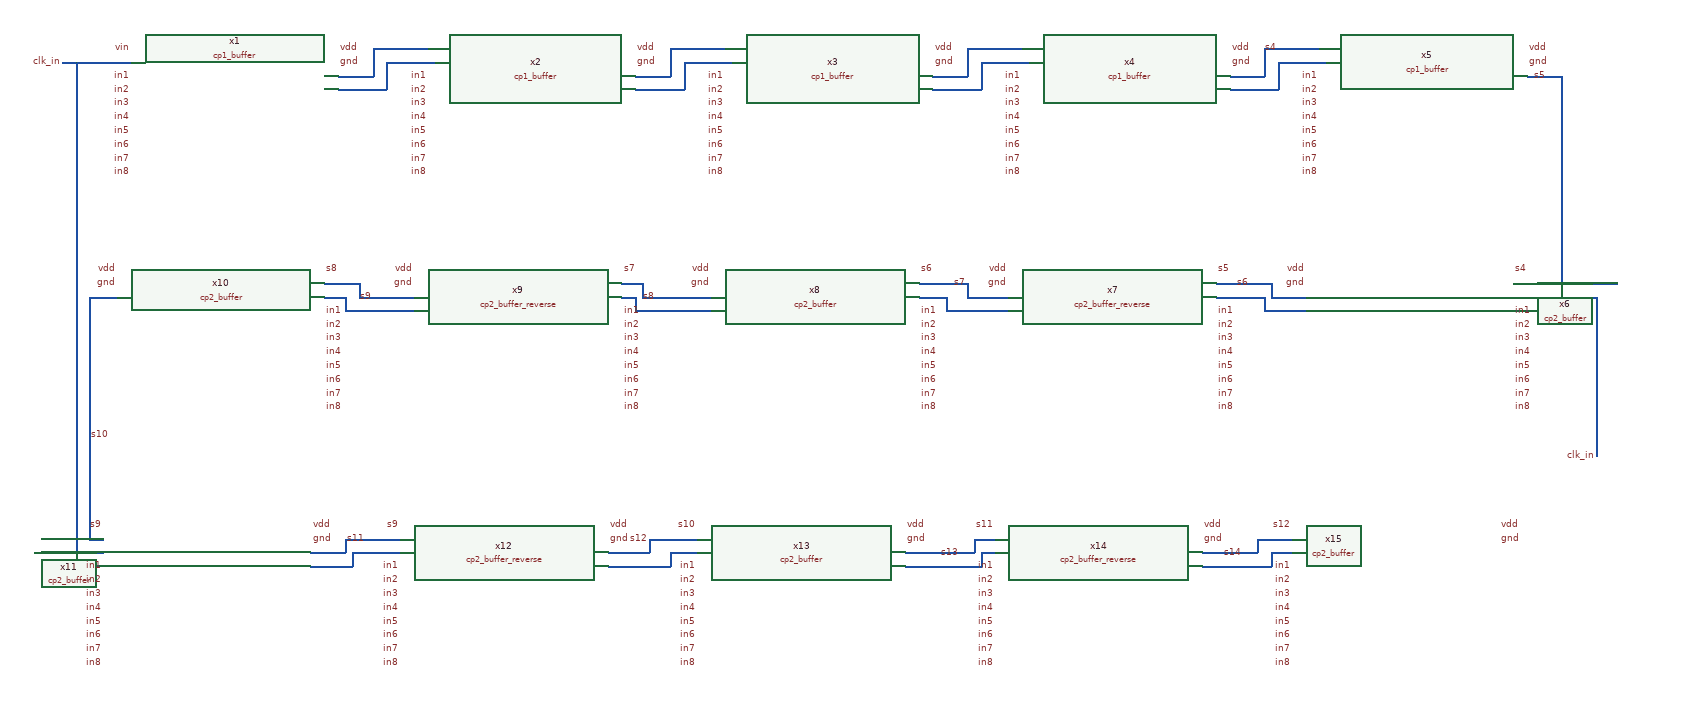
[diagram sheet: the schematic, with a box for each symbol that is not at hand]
v {xschem version=3.4.4 file_version=1.2
}
G {}
K {}
V {}
S {}
E {}
N -1940 -110 -1840 -110 {
lab=clk_in}
N -1540 -90 -1490 -90 {
lab=#net1}
N -1490 -110 -1490 -90 {
lab=#net1}
N -1490 -130 -1490 -110 {
lab=#net1}
N -1490 -130 -1410 -130 {
lab=#net1}
N -1540 -70 -1470 -70 {
lab=#net2}
N -1470 -110 -1470 -70 {
lab=#net2}
N -1470 -110 -1400 -110 {
lab=#net2}
N -1110 -90 -1060 -90 {
lab=#net3}
N -1060 -110 -1060 -90 {
lab=#net3}
N -1060 -130 -1060 -110 {
lab=#net3}
N -1060 -130 -980 -130 {
lab=#net3}
N -1110 -70 -1040 -70 {
lab=#net4}
N -1040 -110 -1040 -70 {
lab=#net4}
N -1040 -110 -970 -110 {
lab=#net4}
N -680 -90 -630 -90 {
lab=#net5}
N -630 -110 -630 -90 {
lab=#net5}
N -630 -130 -630 -110 {
lab=#net5}
N -630 -130 -550 -130 {
lab=#net5}
N -680 -70 -610 -70 {
lab=#net6}
N -610 -110 -610 -70 {
lab=#net6}
N -610 -110 -540 -110 {
lab=#net6}
N -250 -90 -200 -90 {
lab=s4}
N -200 -110 -200 -90 {
lab=s4}
N -200 -130 -200 -110 {
lab=s4}
N -200 -130 -120 -130 {
lab=s4}
N -250 -70 -180 -70 {
lab=#net7}
N -180 -110 -180 -70 {
lab=#net7}
N -180 -110 -110 -110 {
lab=#net7}
N 180 -90 230 -90 {
lab=s5}
N 160 230 260 230 {
lab=clk_in}
N -1510 230 -1430 230 {
lab=s9}
N -1510 210 -1510 230 {
lab=s9}
N -1550 210 -1510 210 {
lab=s9}
N -1560 210 -1550 210 {
lab=s9}
N -1100 230 -1000 230 {
lab=s8}
N -1100 210 -1100 230 {
lab=s8}
N -1130 210 -1100 210 {
lab=s8}
N -1530 250 -1430 250 {
lab=#net8}
N -1530 230 -1530 250 {
lab=#net8}
N -1560 230 -1530 230 {
lab=#net8}
N -1110 250 -1000 250 {
lab=#net9}
N -1110 230 -1110 250 {
lab=#net9}
N -1130 230 -1110 230 {
lab=#net9}
N -660 250 -570 250 {
lab=#net10}
N -660 230 -660 250 {
lab=#net10}
N -700 230 -660 230 {
lab=#net10}
N -200 250 -140 250 {
lab=#net11}
N -200 230 -200 250 {
lab=#net11}
N -270 230 -200 230 {
lab=#net11}
N -270 210 -190 210 {
lab=s6}
N -630 230 -570 230 {
lab=s7}
N -630 210 -630 230 {
lab=s7}
N -700 210 -630 210 {
lab=s7}
N 160 210 310 210 {
lab=s5}
N -190 210 -190 230 {
lab=s6}
N -190 230 -140 230 {
lab=s6}
N 230 -90 230 210 {
lab=s5}
N -1980 600 -1880 600 {
lab=clk_in}
N -290 600 -210 600 {
lab=s14}
N -210 580 -210 600 {
lab=s14}
N -210 580 -170 580 {
lab=s14}
N -170 580 -160 580 {
lab=s14}
N -720 600 -620 600 {
lab=s13}
N -620 580 -620 600 {
lab=s13}
N -620 580 -590 580 {
lab=s13}
N -290 620 -190 620 {
lab=#net12}
N -190 600 -190 620 {
lab=#net12}
N -190 600 -160 600 {
lab=#net12}
N -720 620 -610 620 {
lab=#net13}
N -610 600 -610 620 {
lab=#net13}
N -610 600 -590 600 {
lab=#net13}
N -1150 620 -1060 620 {
lab=#net14}
N -1060 600 -1060 620 {
lab=#net14}
N -1060 600 -1020 600 {
lab=#net14}
N -1580 620 -1520 620 {
lab=#net15}
N -1520 600 -1520 620 {
lab=#net15}
N -1520 600 -1450 600 {
lab=#net15}
N -1530 580 -1450 580 {
lab=s11}
N -1150 600 -1090 600 {
lab=s12}
N -1090 580 -1090 600 {
lab=s12}
N -1090 580 -1020 580 {
lab=s12}
N -1530 580 -1530 600 {
lab=s11}
N -1580 600 -1530 600 {
lab=s11}
N -1920 -110 -1920 600 {
lab=clk_in}
N -1900 230 -1860 230 {
lab=s10}
N -1900 230 -1900 580 {
lab=s10}
N -1900 580 -1880 580 {
lab=s10}
N 280 230 280 460 {
lab=clk_in}
N 260 230 280 230 {
lab=clk_in}
C {cp1_buffer.sym} -1690 -40 0 0 {name=x1}
C {devices/lab_pin.sym} -1840 -90 0 0 {name=p145 sig_type=std_logic lab=in1
value=0}
C {devices/lab_pin.sym} -1840 -70 0 0 {name=p146 sig_type=std_logic lab=in2
value=0}
C {devices/lab_pin.sym} -1840 -50 0 0 {name=p147 sig_type=std_logic lab=in3
value=0}
C {devices/lab_pin.sym} -1840 -30 0 0 {name=p148 sig_type=std_logic lab=in4
value=0}
C {devices/lab_pin.sym} -1840 -10 0 0 {name=p149 sig_type=std_logic lab=in5
value=0}
C {devices/lab_pin.sym} -1840 10 0 0 {name=p150 sig_type=std_logic lab=in6
value=0}
C {devices/lab_pin.sym} -1840 30 0 0 {name=p151 sig_type=std_logic lab=in7
value=0}
C {devices/lab_pin.sym} -1840 50 0 0 {name=p152 sig_type=std_logic lab=in8
value=0}
C {devices/lab_pin.sym} -1840 -130 0 0 {name=p153 sig_type=std_logic lab=vin}
C {devices/lab_pin.sym} -1940 -110 0 0 {name=p1 sig_type=std_logic lab=clk_in}
C {cp1_buffer.sym} -1260 -40 0 0 {name=x2}
C {cp1_buffer.sym} -830 -40 0 0 {name=x3}
C {devices/lab_pin.sym} -980 -90 0 0 {name=p2 sig_type=std_logic lab=in1
value=0}
C {devices/lab_pin.sym} -980 -70 0 0 {name=p3 sig_type=std_logic lab=in2
value=0}
C {devices/lab_pin.sym} -980 -50 0 0 {name=p12 sig_type=std_logic lab=in3
value=0}
C {devices/lab_pin.sym} -980 -30 0 0 {name=p15 sig_type=std_logic lab=in4
value=0}
C {devices/lab_pin.sym} -980 -10 0 0 {name=p16 sig_type=std_logic lab=in5
value=0}
C {devices/lab_pin.sym} -980 10 0 0 {name=p17 sig_type=std_logic lab=in6
value=0}
C {devices/lab_pin.sym} -980 30 0 0 {name=p18 sig_type=std_logic lab=in7
value=0}
C {devices/lab_pin.sym} -980 50 0 0 {name=p19 sig_type=std_logic lab=in8
value=0}
C {devices/lab_pin.sym} -680 -130 2 0 {name=p20 sig_type=std_logic lab=vdd}
C {devices/lab_pin.sym} -680 -110 2 0 {name=p21 sig_type=std_logic lab=gnd}
C {cp1_buffer.sym} -400 -40 0 0 {name=x4}
C {cp1_buffer.sym} 30 -40 0 0 {name=x5}
C {devices/lab_pin.sym} -120 -90 0 0 {name=p28 sig_type=std_logic lab=in1
value=0}
C {devices/lab_pin.sym} -120 -70 0 0 {name=p29 sig_type=std_logic lab=in2
value=0}
C {devices/lab_pin.sym} -120 -50 0 0 {name=p30 sig_type=std_logic lab=in3
value=0}
C {devices/lab_pin.sym} -120 -30 0 0 {name=p31 sig_type=std_logic lab=in4
value=0}
C {devices/lab_pin.sym} -120 -10 0 0 {name=p32 sig_type=std_logic lab=in5
value=0}
C {devices/lab_pin.sym} -120 10 0 0 {name=p33 sig_type=std_logic lab=in6
value=0}
C {devices/lab_pin.sym} -120 30 0 0 {name=p34 sig_type=std_logic lab=in7
value=0}
C {devices/lab_pin.sym} -120 50 0 0 {name=p35 sig_type=std_logic lab=in8
value=0}
C {devices/lab_pin.sym} 180 -130 2 0 {name=p36 sig_type=std_logic lab=vdd}
C {devices/lab_pin.sym} 180 -110 2 0 {name=p37 sig_type=std_logic lab=gnd}
C {devices/lab_pin.sym} -1110 -130 2 0 {name=p38 sig_type=std_logic lab=vdd}
C {devices/lab_pin.sym} -1110 -110 2 0 {name=p39 sig_type=std_logic lab=gnd}
C {devices/lab_pin.sym} -1540 -130 2 0 {name=p40 sig_type=std_logic lab=vdd}
C {devices/lab_pin.sym} -1540 -110 2 0 {name=p41 sig_type=std_logic lab=gnd}
C {devices/lab_pin.sym} -250 -130 2 0 {name=p42 sig_type=std_logic lab=vdd}
C {devices/lab_pin.sym} -250 -110 2 0 {name=p43 sig_type=std_logic lab=gnd}
C {devices/lab_pin.sym} -180 -130 1 0 {name=p52 sig_type=std_logic lab=s4}
C {devices/lab_pin.sym} 210 -90 3 0 {name=p53 sig_type=std_logic lab=s5}
C {devices/lab_pin.sym} -1410 -90 0 0 {name=p188 sig_type=std_logic lab=in1
value=0}
C {devices/lab_pin.sym} -1410 -70 0 0 {name=p189 sig_type=std_logic lab=in2
value=0}
C {devices/lab_pin.sym} -1410 -50 0 0 {name=p190 sig_type=std_logic lab=in3
value=0}
C {devices/lab_pin.sym} -1410 -30 0 0 {name=p191 sig_type=std_logic lab=in4
value=0}
C {devices/lab_pin.sym} -1410 -10 0 0 {name=p192 sig_type=std_logic lab=in5
value=0}
C {devices/lab_pin.sym} -1410 10 0 0 {name=p193 sig_type=std_logic lab=in6
value=0}
C {devices/lab_pin.sym} -1410 30 0 0 {name=p194 sig_type=std_logic lab=in7
value=0}
C {devices/lab_pin.sym} -1410 50 0 0 {name=p195 sig_type=std_logic lab=in8
value=0}
C {devices/lab_pin.sym} -550 -90 0 0 {name=p13 sig_type=std_logic lab=in1
value=0}
C {devices/lab_pin.sym} -550 -70 0 0 {name=p14 sig_type=std_logic lab=in2
value=0}
C {devices/lab_pin.sym} -550 -50 0 0 {name=p22 sig_type=std_logic lab=in3
value=0}
C {devices/lab_pin.sym} -550 -30 0 0 {name=p23 sig_type=std_logic lab=in4
value=0}
C {devices/lab_pin.sym} -550 -10 0 0 {name=p24 sig_type=std_logic lab=in5
value=0}
C {devices/lab_pin.sym} -550 10 0 0 {name=p25 sig_type=std_logic lab=in6
value=0}
C {devices/lab_pin.sym} -550 30 0 0 {name=p26 sig_type=std_logic lab=in7
value=0}
C {devices/lab_pin.sym} -550 50 0 0 {name=p27 sig_type=std_logic lab=in8
value=0}
C {cp2_buffer.sym} 10 290 0 1 {name=x6}
C {devices/lab_pin.sym} 160 250 0 1 {name=p44 sig_type=std_logic lab=in1
value=0}
C {devices/lab_pin.sym} 160 270 0 1 {name=p45 sig_type=std_logic lab=in2
value=0}
C {devices/lab_pin.sym} 160 290 0 1 {name=p46 sig_type=std_logic lab=in3
value=0}
C {devices/lab_pin.sym} 160 310 0 1 {name=p47 sig_type=std_logic lab=in4
value=0}
C {devices/lab_pin.sym} 160 330 0 1 {name=p48 sig_type=std_logic lab=in5
value=0}
C {devices/lab_pin.sym} 160 350 0 1 {name=p49 sig_type=std_logic lab=in6
value=0}
C {devices/lab_pin.sym} 160 370 0 1 {name=p50 sig_type=std_logic lab=in7
value=0}
C {devices/lab_pin.sym} 160 390 0 1 {name=p51 sig_type=std_logic lab=in8
value=0}
C {cp2_buffer_reverse.sym} -420 290 0 1 {name=x7}
C {devices/lab_pin.sym} -270 250 0 1 {name=p54 sig_type=std_logic lab=in1
value=0}
C {devices/lab_pin.sym} -270 270 0 1 {name=p55 sig_type=std_logic lab=in2
value=0}
C {devices/lab_pin.sym} -270 290 0 1 {name=p56 sig_type=std_logic lab=in3
value=0}
C {devices/lab_pin.sym} -270 310 0 1 {name=p57 sig_type=std_logic lab=in4
value=0}
C {devices/lab_pin.sym} -270 330 0 1 {name=p58 sig_type=std_logic lab=in5
value=0}
C {devices/lab_pin.sym} -270 350 0 1 {name=p59 sig_type=std_logic lab=in6
value=0}
C {devices/lab_pin.sym} -270 370 0 1 {name=p60 sig_type=std_logic lab=in7
value=0}
C {devices/lab_pin.sym} -270 390 0 1 {name=p61 sig_type=std_logic lab=in8
value=0}
C {cp2_buffer.sym} -850 290 0 1 {name=x8}
C {devices/lab_pin.sym} -700 250 0 1 {name=p62 sig_type=std_logic lab=in1
value=0}
C {devices/lab_pin.sym} -700 270 0 1 {name=p63 sig_type=std_logic lab=in2
value=0}
C {devices/lab_pin.sym} -700 290 0 1 {name=p64 sig_type=std_logic lab=in3
value=0}
C {devices/lab_pin.sym} -700 310 0 1 {name=p65 sig_type=std_logic lab=in4
value=0}
C {devices/lab_pin.sym} -700 330 0 1 {name=p66 sig_type=std_logic lab=in5
value=0}
C {devices/lab_pin.sym} -700 350 0 1 {name=p67 sig_type=std_logic lab=in6
value=0}
C {devices/lab_pin.sym} -700 370 0 1 {name=p68 sig_type=std_logic lab=in7
value=0}
C {devices/lab_pin.sym} -700 390 0 1 {name=p69 sig_type=std_logic lab=in8
value=0}
C {devices/lab_pin.sym} -1000 190 2 1 {name=p70 sig_type=std_logic lab=vdd}
C {devices/lab_pin.sym} -1000 210 2 1 {name=p71 sig_type=std_logic lab=gnd}
C {cp2_buffer_reverse.sym} -1280 290 0 1 {name=x9}
C {devices/lab_pin.sym} -1130 250 0 1 {name=p72 sig_type=std_logic lab=in1
value=0}
C {devices/lab_pin.sym} -1130 270 0 1 {name=p73 sig_type=std_logic lab=in2
value=0}
C {devices/lab_pin.sym} -1130 290 0 1 {name=p74 sig_type=std_logic lab=in3
value=0}
C {devices/lab_pin.sym} -1130 310 0 1 {name=p75 sig_type=std_logic lab=in4
value=0}
C {devices/lab_pin.sym} -1130 330 0 1 {name=p76 sig_type=std_logic lab=in5
value=0}
C {devices/lab_pin.sym} -1130 350 0 1 {name=p77 sig_type=std_logic lab=in6
value=0}
C {devices/lab_pin.sym} -1130 370 0 1 {name=p78 sig_type=std_logic lab=in7
value=0}
C {devices/lab_pin.sym} -1130 390 0 1 {name=p79 sig_type=std_logic lab=in8
value=0}
C {cp2_buffer.sym} -1710 290 0 1 {name=x10}
C {devices/lab_pin.sym} -1560 250 0 1 {name=p80 sig_type=std_logic lab=in1
value=0}
C {devices/lab_pin.sym} -1560 270 0 1 {name=p81 sig_type=std_logic lab=in2
value=0}
C {devices/lab_pin.sym} -1560 290 0 1 {name=p82 sig_type=std_logic lab=in3
value=0}
C {devices/lab_pin.sym} -1560 310 0 1 {name=p83 sig_type=std_logic lab=in4
value=0}
C {devices/lab_pin.sym} -1560 330 0 1 {name=p84 sig_type=std_logic lab=in5
value=0}
C {devices/lab_pin.sym} -1560 350 0 1 {name=p85 sig_type=std_logic lab=in6
value=0}
C {devices/lab_pin.sym} -1560 370 0 1 {name=p86 sig_type=std_logic lab=in7
value=0}
C {devices/lab_pin.sym} -1560 390 0 1 {name=p87 sig_type=std_logic lab=in8
value=0}
C {devices/lab_pin.sym} -1860 190 2 1 {name=p88 sig_type=std_logic lab=vdd}
C {devices/lab_pin.sym} -1860 210 2 1 {name=p89 sig_type=std_logic lab=gnd}
C {devices/lab_pin.sym} -570 190 2 1 {name=p90 sig_type=std_logic lab=vdd}
C {devices/lab_pin.sym} -570 210 2 1 {name=p91 sig_type=std_logic lab=gnd}
C {devices/lab_pin.sym} -140 190 2 1 {name=p92 sig_type=std_logic lab=vdd}
C {devices/lab_pin.sym} -140 210 2 1 {name=p93 sig_type=std_logic lab=gnd}
C {devices/lab_pin.sym} -1430 190 2 1 {name=p94 sig_type=std_logic lab=vdd}
C {devices/lab_pin.sym} -1430 210 2 1 {name=p95 sig_type=std_logic lab=gnd}
C {devices/lab_pin.sym} -220 210 1 0 {name=p104 sig_type=std_logic lab=s6}
C {devices/lab_pin.sym} -630 210 1 0 {name=p157 sig_type=std_logic lab=s7}
C {devices/lab_pin.sym} -1080 230 1 0 {name=p158 sig_type=std_logic lab=s8}
C {devices/lab_pin.sym} -1490 230 1 0 {name=p159 sig_type=std_logic lab=s9}
C {devices/lab_pin.sym} 160 190 2 0 {name=p6 sig_type=std_logic lab=s4}
C {devices/lab_pin.sym} -270 190 2 0 {name=p8 sig_type=std_logic lab=s5}
C {devices/lab_pin.sym} -700 190 2 0 {name=p9 sig_type=std_logic lab=s6}
C {devices/lab_pin.sym} -1130 190 2 0 {name=p10 sig_type=std_logic lab=s7}
C {devices/lab_pin.sym} -1560 190 2 0 {name=p11 sig_type=std_logic lab=s8}
C {cp2_buffer.sym} -1730 660 0 0 {name=x11}
C {devices/lab_pin.sym} -1880 620 0 0 {name=p4 sig_type=std_logic lab=in1
value=0}
C {devices/lab_pin.sym} -1880 640 0 0 {name=p5 sig_type=std_logic lab=in2
value=0}
C {devices/lab_pin.sym} -1880 660 0 0 {name=p7 sig_type=std_logic lab=in3
value=0}
C {devices/lab_pin.sym} -1880 680 0 0 {name=p96 sig_type=std_logic lab=in4
value=0}
C {devices/lab_pin.sym} -1880 700 0 0 {name=p97 sig_type=std_logic lab=in5
value=0}
C {devices/lab_pin.sym} -1880 720 0 0 {name=p98 sig_type=std_logic lab=in6
value=0}
C {devices/lab_pin.sym} -1880 740 0 0 {name=p99 sig_type=std_logic lab=in7
value=0}
C {devices/lab_pin.sym} -1880 760 0 0 {name=p100 sig_type=std_logic lab=in8
value=0}
C {cp2_buffer_reverse.sym} -1300 660 0 0 {name=x12}
C {devices/lab_pin.sym} -1450 620 0 0 {name=p101 sig_type=std_logic lab=in1
value=0}
C {devices/lab_pin.sym} -1450 640 0 0 {name=p102 sig_type=std_logic lab=in2
value=0}
C {devices/lab_pin.sym} -1450 660 0 0 {name=p103 sig_type=std_logic lab=in3
value=0}
C {devices/lab_pin.sym} -1450 680 0 0 {name=p105 sig_type=std_logic lab=in4
value=0}
C {devices/lab_pin.sym} -1450 700 0 0 {name=p106 sig_type=std_logic lab=in5
value=0}
C {devices/lab_pin.sym} -1450 720 0 0 {name=p107 sig_type=std_logic lab=in6
value=0}
C {devices/lab_pin.sym} -1450 740 0 0 {name=p108 sig_type=std_logic lab=in7
value=0}
C {devices/lab_pin.sym} -1450 760 0 0 {name=p109 sig_type=std_logic lab=in8
value=0}
C {cp2_buffer.sym} -870 660 0 0 {name=x13}
C {devices/lab_pin.sym} -1020 620 0 0 {name=p110 sig_type=std_logic lab=in1
value=0}
C {devices/lab_pin.sym} -1020 640 0 0 {name=p111 sig_type=std_logic lab=in2
value=0}
C {devices/lab_pin.sym} -1020 660 0 0 {name=p112 sig_type=std_logic lab=in3
value=0}
C {devices/lab_pin.sym} -1020 680 0 0 {name=p113 sig_type=std_logic lab=in4
value=0}
C {devices/lab_pin.sym} -1020 700 0 0 {name=p114 sig_type=std_logic lab=in5
value=0}
C {devices/lab_pin.sym} -1020 720 0 0 {name=p115 sig_type=std_logic lab=in6
value=0}
C {devices/lab_pin.sym} -1020 740 0 0 {name=p116 sig_type=std_logic lab=in7
value=0}
C {devices/lab_pin.sym} -1020 760 0 0 {name=p117 sig_type=std_logic lab=in8
value=0}
C {devices/lab_pin.sym} -720 560 2 0 {name=p118 sig_type=std_logic lab=vdd}
C {devices/lab_pin.sym} -720 580 2 0 {name=p119 sig_type=std_logic lab=gnd}
C {cp2_buffer_reverse.sym} -440 660 0 0 {name=x14}
C {devices/lab_pin.sym} -590 620 0 0 {name=p120 sig_type=std_logic lab=in1
value=0}
C {devices/lab_pin.sym} -590 640 0 0 {name=p121 sig_type=std_logic lab=in2
value=0}
C {devices/lab_pin.sym} -590 660 0 0 {name=p122 sig_type=std_logic lab=in3
value=0}
C {devices/lab_pin.sym} -590 680 0 0 {name=p123 sig_type=std_logic lab=in4
value=0}
C {devices/lab_pin.sym} -590 700 0 0 {name=p124 sig_type=std_logic lab=in5
value=0}
C {devices/lab_pin.sym} -590 720 0 0 {name=p125 sig_type=std_logic lab=in6
value=0}
C {devices/lab_pin.sym} -590 740 0 0 {name=p126 sig_type=std_logic lab=in7
value=0}
C {devices/lab_pin.sym} -590 760 0 0 {name=p127 sig_type=std_logic lab=in8
value=0}
C {cp2_buffer.sym} -10 660 0 0 {name=x15}
C {devices/lab_pin.sym} -160 620 0 0 {name=p128 sig_type=std_logic lab=in1
value=0}
C {devices/lab_pin.sym} -160 640 0 0 {name=p129 sig_type=std_logic lab=in2
value=0}
C {devices/lab_pin.sym} -160 660 0 0 {name=p130 sig_type=std_logic lab=in3
value=0}
C {devices/lab_pin.sym} -160 680 0 0 {name=p131 sig_type=std_logic lab=in4
value=0}
C {devices/lab_pin.sym} -160 700 0 0 {name=p132 sig_type=std_logic lab=in5
value=0}
C {devices/lab_pin.sym} -160 720 0 0 {name=p133 sig_type=std_logic lab=in6
value=0}
C {devices/lab_pin.sym} -160 740 0 0 {name=p134 sig_type=std_logic lab=in7
value=0}
C {devices/lab_pin.sym} -160 760 0 0 {name=p135 sig_type=std_logic lab=in8
value=0}
C {devices/lab_pin.sym} 140 560 2 0 {name=p136 sig_type=std_logic lab=vdd}
C {devices/lab_pin.sym} 140 580 2 0 {name=p137 sig_type=std_logic lab=gnd}
C {devices/lab_pin.sym} -1150 560 2 0 {name=p138 sig_type=std_logic lab=vdd}
C {devices/lab_pin.sym} -1150 580 2 0 {name=p139 sig_type=std_logic lab=gnd}
C {devices/lab_pin.sym} -1580 560 2 0 {name=p140 sig_type=std_logic lab=vdd}
C {devices/lab_pin.sym} -1580 580 2 0 {name=p141 sig_type=std_logic lab=gnd}
C {devices/lab_pin.sym} -290 560 2 0 {name=p142 sig_type=std_logic lab=vdd}
C {devices/lab_pin.sym} -290 580 2 0 {name=p143 sig_type=std_logic lab=gnd}
C {devices/lab_pin.sym} -1500 580 3 1 {name=p144 sig_type=std_logic lab=s11}
C {devices/lab_pin.sym} -1090 580 3 1 {name=p154 sig_type=std_logic lab=s12}
C {devices/lab_pin.sym} -640 600 3 1 {name=p155 sig_type=std_logic lab=s13}
C {devices/lab_pin.sym} -230 600 3 1 {name=p156 sig_type=std_logic lab=s14}
C {devices/lab_pin.sym} -1880 560 2 1 {name=p160 sig_type=std_logic lab=s9}
C {devices/lab_pin.sym} -1450 560 2 1 {name=p161 sig_type=std_logic lab=s9}
C {devices/lab_pin.sym} -1020 560 2 1 {name=p162 sig_type=std_logic lab=s10}
C {devices/lab_pin.sym} -590 560 2 1 {name=p163 sig_type=std_logic lab=s11}
C {devices/lab_pin.sym} -160 560 2 1 {name=p164 sig_type=std_logic lab=s12}
C {devices/lab_pin.sym} -1900 430 2 0 {name=p165 sig_type=std_logic lab=s10}
C {devices/lab_pin.sym} 280 460 3 0 {name=p166 sig_type=std_logic lab=clk_in}
